VERSION 5.7 ;
BUSBITCHARS "[]" ;
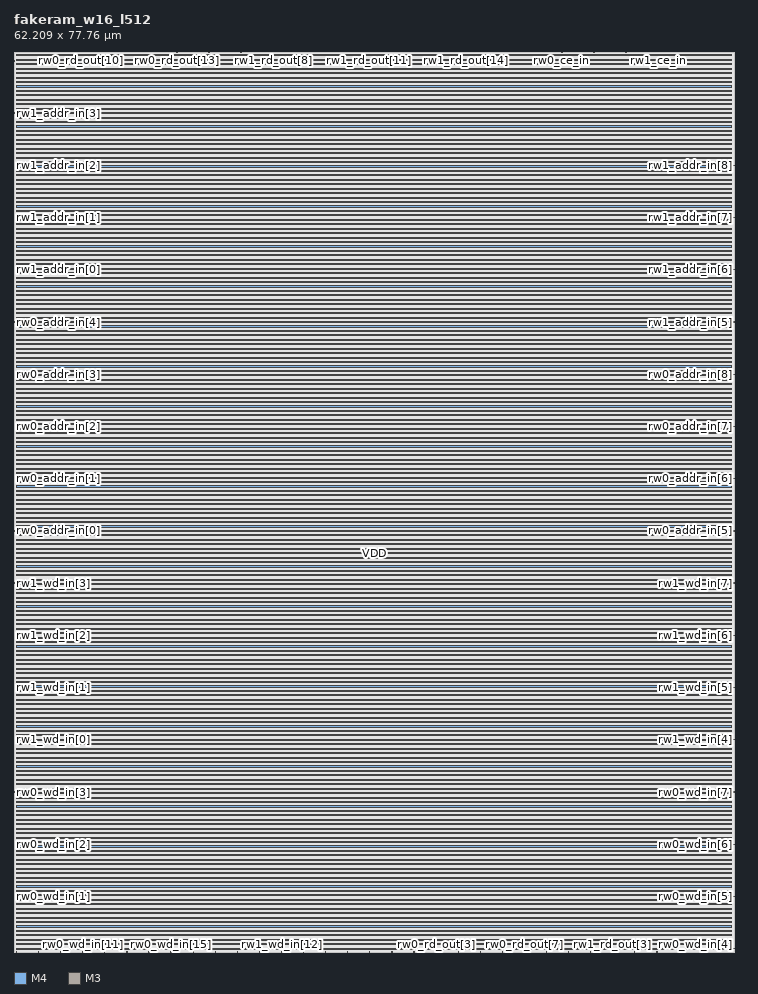
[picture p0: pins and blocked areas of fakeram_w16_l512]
MACRO fakeram_w16_l512
  FOREIGN fakeram_w16_l512 0 0 ;
  SYMMETRY X Y R90 ;
  SIZE 62.209 BY 77.760 ;
  CLASS BLOCK ;
  PIN rw0_wd_in[0]
    DIRECTION INPUT ;
    USE SIGNAL ;
    SHAPE ABUTMENT ;
    PORT
      LAYER M4 ;
      RECT 0.000 0.276 0.072 0.300 ;
    END
  END rw0_wd_in[0]
  PIN rw0_wd_in[1]
    DIRECTION INPUT ;
    USE SIGNAL ;
    SHAPE ABUTMENT ;
    PORT
      LAYER M4 ;
      RECT 0.000 4.788 0.072 4.812 ;
    END
  END rw0_wd_in[1]
  PIN rw0_wd_in[2]
    DIRECTION INPUT ;
    USE SIGNAL ;
    SHAPE ABUTMENT ;
    PORT
      LAYER M4 ;
      RECT 0.000 9.300 0.072 9.324 ;
    END
  END rw0_wd_in[2]
  PIN rw0_wd_in[3]
    DIRECTION INPUT ;
    USE SIGNAL ;
    SHAPE ABUTMENT ;
    PORT
      LAYER M4 ;
      RECT 0.000 13.812 0.072 13.836 ;
    END
  END rw0_wd_in[3]
  PIN rw0_wd_in[4]
    DIRECTION INPUT ;
    USE SIGNAL ;
    SHAPE ABUTMENT ;
    PORT
      LAYER M4 ;
      RECT 62.137 0.276 62.209 0.300 ;
    END
  END rw0_wd_in[4]
  PIN rw0_wd_in[5]
    DIRECTION INPUT ;
    USE SIGNAL ;
    SHAPE ABUTMENT ;
    PORT
      LAYER M4 ;
      RECT 62.137 4.788 62.209 4.812 ;
    END
  END rw0_wd_in[5]
  PIN rw0_wd_in[6]
    DIRECTION INPUT ;
    USE SIGNAL ;
    SHAPE ABUTMENT ;
    PORT
      LAYER M4 ;
      RECT 62.137 9.300 62.209 9.324 ;
    END
  END rw0_wd_in[6]
  PIN rw0_wd_in[7]
    DIRECTION INPUT ;
    USE SIGNAL ;
    SHAPE ABUTMENT ;
    PORT
      LAYER M4 ;
      RECT 62.137 13.812 62.209 13.836 ;
    END
  END rw0_wd_in[7]
  PIN rw0_wd_in[8]
    DIRECTION INPUT ;
    USE SIGNAL ;
    SHAPE ABUTMENT ;
    PORT
      LAYER M3 ;
      RECT 0.207 0.000 0.225 0.054 ;
    END
  END rw0_wd_in[8]
  PIN rw0_wd_in[9]
    DIRECTION INPUT ;
    USE SIGNAL ;
    SHAPE ABUTMENT ;
    PORT
      LAYER M3 ;
      RECT 2.115 0.000 2.133 0.054 ;
    END
  END rw0_wd_in[9]
  PIN rw0_wd_in[10]
    DIRECTION INPUT ;
    USE SIGNAL ;
    SHAPE ABUTMENT ;
    PORT
      LAYER M3 ;
      RECT 4.023 0.000 4.041 0.054 ;
    END
  END rw0_wd_in[10]
  PIN rw0_wd_in[11]
    DIRECTION INPUT ;
    USE SIGNAL ;
    SHAPE ABUTMENT ;
    PORT
      LAYER M3 ;
      RECT 5.931 0.000 5.949 0.054 ;
    END
  END rw0_wd_in[11]
  PIN rw0_wd_in[12]
    DIRECTION INPUT ;
    USE SIGNAL ;
    SHAPE ABUTMENT ;
    PORT
      LAYER M3 ;
      RECT 7.839 0.000 7.857 0.054 ;
    END
  END rw0_wd_in[12]
  PIN rw0_wd_in[13]
    DIRECTION INPUT ;
    USE SIGNAL ;
    SHAPE ABUTMENT ;
    PORT
      LAYER M3 ;
      RECT 9.747 0.000 9.765 0.054 ;
    END
  END rw0_wd_in[13]
  PIN rw0_wd_in[14]
    DIRECTION INPUT ;
    USE SIGNAL ;
    SHAPE ABUTMENT ;
    PORT
      LAYER M3 ;
      RECT 11.655 0.000 11.673 0.054 ;
    END
  END rw0_wd_in[14]
  PIN rw0_wd_in[15]
    DIRECTION INPUT ;
    USE SIGNAL ;
    SHAPE ABUTMENT ;
    PORT
      LAYER M3 ;
      RECT 13.563 0.000 13.581 0.054 ;
    END
  END rw0_wd_in[15]
  PIN rw1_wd_in[0]
    DIRECTION INPUT ;
    USE SIGNAL ;
    SHAPE ABUTMENT ;
    PORT
      LAYER M4 ;
      RECT 0.000 18.324 0.072 18.348 ;
    END
  END rw1_wd_in[0]
  PIN rw1_wd_in[1]
    DIRECTION INPUT ;
    USE SIGNAL ;
    SHAPE ABUTMENT ;
    PORT
      LAYER M4 ;
      RECT 0.000 22.836 0.072 22.860 ;
    END
  END rw1_wd_in[1]
  PIN rw1_wd_in[2]
    DIRECTION INPUT ;
    USE SIGNAL ;
    SHAPE ABUTMENT ;
    PORT
      LAYER M4 ;
      RECT 0.000 27.348 0.072 27.372 ;
    END
  END rw1_wd_in[2]
  PIN rw1_wd_in[3]
    DIRECTION INPUT ;
    USE SIGNAL ;
    SHAPE ABUTMENT ;
    PORT
      LAYER M4 ;
      RECT 0.000 31.860 0.072 31.884 ;
    END
  END rw1_wd_in[3]
  PIN rw1_wd_in[4]
    DIRECTION INPUT ;
    USE SIGNAL ;
    SHAPE ABUTMENT ;
    PORT
      LAYER M4 ;
      RECT 62.137 18.324 62.209 18.348 ;
    END
  END rw1_wd_in[4]
  PIN rw1_wd_in[5]
    DIRECTION INPUT ;
    USE SIGNAL ;
    SHAPE ABUTMENT ;
    PORT
      LAYER M4 ;
      RECT 62.137 22.836 62.209 22.860 ;
    END
  END rw1_wd_in[5]
  PIN rw1_wd_in[6]
    DIRECTION INPUT ;
    USE SIGNAL ;
    SHAPE ABUTMENT ;
    PORT
      LAYER M4 ;
      RECT 62.137 27.348 62.209 27.372 ;
    END
  END rw1_wd_in[6]
  PIN rw1_wd_in[7]
    DIRECTION INPUT ;
    USE SIGNAL ;
    SHAPE ABUTMENT ;
    PORT
      LAYER M4 ;
      RECT 62.137 31.860 62.209 31.884 ;
    END
  END rw1_wd_in[7]
  PIN rw1_wd_in[8]
    DIRECTION INPUT ;
    USE SIGNAL ;
    SHAPE ABUTMENT ;
    PORT
      LAYER M3 ;
      RECT 15.471 0.000 15.489 0.054 ;
    END
  END rw1_wd_in[8]
  PIN rw1_wd_in[9]
    DIRECTION INPUT ;
    USE SIGNAL ;
    SHAPE ABUTMENT ;
    PORT
      LAYER M3 ;
      RECT 17.379 0.000 17.397 0.054 ;
    END
  END rw1_wd_in[9]
  PIN rw1_wd_in[10]
    DIRECTION INPUT ;
    USE SIGNAL ;
    SHAPE ABUTMENT ;
    PORT
      LAYER M3 ;
      RECT 19.287 0.000 19.305 0.054 ;
    END
  END rw1_wd_in[10]
  PIN rw1_wd_in[11]
    DIRECTION INPUT ;
    USE SIGNAL ;
    SHAPE ABUTMENT ;
    PORT
      LAYER M3 ;
      RECT 21.195 0.000 21.213 0.054 ;
    END
  END rw1_wd_in[11]
  PIN rw1_wd_in[12]
    DIRECTION INPUT ;
    USE SIGNAL ;
    SHAPE ABUTMENT ;
    PORT
      LAYER M3 ;
      RECT 23.103 0.000 23.121 0.054 ;
    END
  END rw1_wd_in[12]
  PIN rw1_wd_in[13]
    DIRECTION INPUT ;
    USE SIGNAL ;
    SHAPE ABUTMENT ;
    PORT
      LAYER M3 ;
      RECT 25.011 0.000 25.029 0.054 ;
    END
  END rw1_wd_in[13]
  PIN rw1_wd_in[14]
    DIRECTION INPUT ;
    USE SIGNAL ;
    SHAPE ABUTMENT ;
    PORT
      LAYER M3 ;
      RECT 26.919 0.000 26.937 0.054 ;
    END
  END rw1_wd_in[14]
  PIN rw1_wd_in[15]
    DIRECTION INPUT ;
    USE SIGNAL ;
    SHAPE ABUTMENT ;
    PORT
      LAYER M3 ;
      RECT 28.827 0.000 28.845 0.054 ;
    END
  END rw1_wd_in[15]
  PIN rw0_rd_out[0]
    DIRECTION OUTPUT ;
    USE SIGNAL ;
    SHAPE ABUTMENT ;
    PORT
      LAYER M3 ;
      RECT 30.735 0.000 30.753 0.054 ;
    END
  END rw0_rd_out[0]
  PIN rw0_rd_out[1]
    DIRECTION OUTPUT ;
    USE SIGNAL ;
    SHAPE ABUTMENT ;
    PORT
      LAYER M3 ;
      RECT 32.643 0.000 32.661 0.054 ;
    END
  END rw0_rd_out[1]
  PIN rw0_rd_out[2]
    DIRECTION OUTPUT ;
    USE SIGNAL ;
    SHAPE ABUTMENT ;
    PORT
      LAYER M3 ;
      RECT 34.551 0.000 34.569 0.054 ;
    END
  END rw0_rd_out[2]
  PIN rw0_rd_out[3]
    DIRECTION OUTPUT ;
    USE SIGNAL ;
    SHAPE ABUTMENT ;
    PORT
      LAYER M3 ;
      RECT 36.459 0.000 36.477 0.054 ;
    END
  END rw0_rd_out[3]
  PIN rw0_rd_out[4]
    DIRECTION OUTPUT ;
    USE SIGNAL ;
    SHAPE ABUTMENT ;
    PORT
      LAYER M3 ;
      RECT 38.367 0.000 38.385 0.054 ;
    END
  END rw0_rd_out[4]
  PIN rw0_rd_out[5]
    DIRECTION OUTPUT ;
    USE SIGNAL ;
    SHAPE ABUTMENT ;
    PORT
      LAYER M3 ;
      RECT 40.275 0.000 40.293 0.054 ;
    END
  END rw0_rd_out[5]
  PIN rw0_rd_out[6]
    DIRECTION OUTPUT ;
    USE SIGNAL ;
    SHAPE ABUTMENT ;
    PORT
      LAYER M3 ;
      RECT 42.183 0.000 42.201 0.054 ;
    END
  END rw0_rd_out[6]
  PIN rw0_rd_out[7]
    DIRECTION OUTPUT ;
    USE SIGNAL ;
    SHAPE ABUTMENT ;
    PORT
      LAYER M3 ;
      RECT 44.091 0.000 44.109 0.054 ;
    END
  END rw0_rd_out[7]
  PIN rw0_rd_out[8]
    DIRECTION OUTPUT ;
    USE SIGNAL ;
    SHAPE ABUTMENT ;
    PORT
      LAYER M3 ;
      RECT 0.207 77.706 0.225 77.760 ;
    END
  END rw0_rd_out[8]
  PIN rw0_rd_out[9]
    DIRECTION OUTPUT ;
    USE SIGNAL ;
    SHAPE ABUTMENT ;
    PORT
      LAYER M3 ;
      RECT 2.979 77.706 2.997 77.760 ;
    END
  END rw0_rd_out[9]
  PIN rw0_rd_out[10]
    DIRECTION OUTPUT ;
    USE SIGNAL ;
    SHAPE ABUTMENT ;
    PORT
      LAYER M3 ;
      RECT 5.751 77.706 5.769 77.760 ;
    END
  END rw0_rd_out[10]
  PIN rw0_rd_out[11]
    DIRECTION OUTPUT ;
    USE SIGNAL ;
    SHAPE ABUTMENT ;
    PORT
      LAYER M3 ;
      RECT 8.523 77.706 8.541 77.760 ;
    END
  END rw0_rd_out[11]
  PIN rw0_rd_out[12]
    DIRECTION OUTPUT ;
    USE SIGNAL ;
    SHAPE ABUTMENT ;
    PORT
      LAYER M3 ;
      RECT 11.295 77.706 11.313 77.760 ;
    END
  END rw0_rd_out[12]
  PIN rw0_rd_out[13]
    DIRECTION OUTPUT ;
    USE SIGNAL ;
    SHAPE ABUTMENT ;
    PORT
      LAYER M3 ;
      RECT 14.067 77.706 14.085 77.760 ;
    END
  END rw0_rd_out[13]
  PIN rw0_rd_out[14]
    DIRECTION OUTPUT ;
    USE SIGNAL ;
    SHAPE ABUTMENT ;
    PORT
      LAYER M3 ;
      RECT 16.839 77.706 16.857 77.760 ;
    END
  END rw0_rd_out[14]
  PIN rw0_rd_out[15]
    DIRECTION OUTPUT ;
    USE SIGNAL ;
    SHAPE ABUTMENT ;
    PORT
      LAYER M3 ;
      RECT 19.611 77.706 19.629 77.760 ;
    END
  END rw0_rd_out[15]
  PIN rw1_rd_out[0]
    DIRECTION OUTPUT ;
    USE SIGNAL ;
    SHAPE ABUTMENT ;
    PORT
      LAYER M3 ;
      RECT 45.999 0.000 46.017 0.054 ;
    END
  END rw1_rd_out[0]
  PIN rw1_rd_out[1]
    DIRECTION OUTPUT ;
    USE SIGNAL ;
    SHAPE ABUTMENT ;
    PORT
      LAYER M3 ;
      RECT 47.907 0.000 47.925 0.054 ;
    END
  END rw1_rd_out[1]
  PIN rw1_rd_out[2]
    DIRECTION OUTPUT ;
    USE SIGNAL ;
    SHAPE ABUTMENT ;
    PORT
      LAYER M3 ;
      RECT 49.815 0.000 49.833 0.054 ;
    END
  END rw1_rd_out[2]
  PIN rw1_rd_out[3]
    DIRECTION OUTPUT ;
    USE SIGNAL ;
    SHAPE ABUTMENT ;
    PORT
      LAYER M3 ;
      RECT 51.723 0.000 51.741 0.054 ;
    END
  END rw1_rd_out[3]
  PIN rw1_rd_out[4]
    DIRECTION OUTPUT ;
    USE SIGNAL ;
    SHAPE ABUTMENT ;
    PORT
      LAYER M3 ;
      RECT 53.631 0.000 53.649 0.054 ;
    END
  END rw1_rd_out[4]
  PIN rw1_rd_out[5]
    DIRECTION OUTPUT ;
    USE SIGNAL ;
    SHAPE ABUTMENT ;
    PORT
      LAYER M3 ;
      RECT 55.539 0.000 55.557 0.054 ;
    END
  END rw1_rd_out[5]
  PIN rw1_rd_out[6]
    DIRECTION OUTPUT ;
    USE SIGNAL ;
    SHAPE ABUTMENT ;
    PORT
      LAYER M3 ;
      RECT 57.447 0.000 57.465 0.054 ;
    END
  END rw1_rd_out[6]
  PIN rw1_rd_out[7]
    DIRECTION OUTPUT ;
    USE SIGNAL ;
    SHAPE ABUTMENT ;
    PORT
      LAYER M3 ;
      RECT 59.355 0.000 59.373 0.054 ;
    END
  END rw1_rd_out[7]
  PIN rw1_rd_out[8]
    DIRECTION OUTPUT ;
    USE SIGNAL ;
    SHAPE ABUTMENT ;
    PORT
      LAYER M3 ;
      RECT 22.383 77.706 22.401 77.760 ;
    END
  END rw1_rd_out[8]
  PIN rw1_rd_out[9]
    DIRECTION OUTPUT ;
    USE SIGNAL ;
    SHAPE ABUTMENT ;
    PORT
      LAYER M3 ;
      RECT 25.155 77.706 25.173 77.760 ;
    END
  END rw1_rd_out[9]
  PIN rw1_rd_out[10]
    DIRECTION OUTPUT ;
    USE SIGNAL ;
    SHAPE ABUTMENT ;
    PORT
      LAYER M3 ;
      RECT 27.927 77.706 27.945 77.760 ;
    END
  END rw1_rd_out[10]
  PIN rw1_rd_out[11]
    DIRECTION OUTPUT ;
    USE SIGNAL ;
    SHAPE ABUTMENT ;
    PORT
      LAYER M3 ;
      RECT 30.699 77.706 30.717 77.760 ;
    END
  END rw1_rd_out[11]
  PIN rw1_rd_out[12]
    DIRECTION OUTPUT ;
    USE SIGNAL ;
    SHAPE ABUTMENT ;
    PORT
      LAYER M3 ;
      RECT 33.471 77.706 33.489 77.760 ;
    END
  END rw1_rd_out[12]
  PIN rw1_rd_out[13]
    DIRECTION OUTPUT ;
    USE SIGNAL ;
    SHAPE ABUTMENT ;
    PORT
      LAYER M3 ;
      RECT 36.243 77.706 36.261 77.760 ;
    END
  END rw1_rd_out[13]
  PIN rw1_rd_out[14]
    DIRECTION OUTPUT ;
    USE SIGNAL ;
    SHAPE ABUTMENT ;
    PORT
      LAYER M3 ;
      RECT 39.015 77.706 39.033 77.760 ;
    END
  END rw1_rd_out[14]
  PIN rw1_rd_out[15]
    DIRECTION OUTPUT ;
    USE SIGNAL ;
    SHAPE ABUTMENT ;
    PORT
      LAYER M3 ;
      RECT 41.787 77.706 41.805 77.760 ;
    END
  END rw1_rd_out[15]
  PIN rw0_addr_in[0]
    DIRECTION INPUT ;
    USE SIGNAL ;
    SHAPE ABUTMENT ;
    PORT
      LAYER M4 ;
      RECT 0.000 36.372 0.072 36.396 ;
    END
  END rw0_addr_in[0]
  PIN rw0_addr_in[1]
    DIRECTION INPUT ;
    USE SIGNAL ;
    SHAPE ABUTMENT ;
    PORT
      LAYER M4 ;
      RECT 0.000 40.884 0.072 40.908 ;
    END
  END rw0_addr_in[1]
  PIN rw0_addr_in[2]
    DIRECTION INPUT ;
    USE SIGNAL ;
    SHAPE ABUTMENT ;
    PORT
      LAYER M4 ;
      RECT 0.000 45.396 0.072 45.420 ;
    END
  END rw0_addr_in[2]
  PIN rw0_addr_in[3]
    DIRECTION INPUT ;
    USE SIGNAL ;
    SHAPE ABUTMENT ;
    PORT
      LAYER M4 ;
      RECT 0.000 49.908 0.072 49.932 ;
    END
  END rw0_addr_in[3]
  PIN rw0_addr_in[4]
    DIRECTION INPUT ;
    USE SIGNAL ;
    SHAPE ABUTMENT ;
    PORT
      LAYER M4 ;
      RECT 0.000 54.420 0.072 54.444 ;
    END
  END rw0_addr_in[4]
  PIN rw0_addr_in[5]
    DIRECTION INPUT ;
    USE SIGNAL ;
    SHAPE ABUTMENT ;
    PORT
      LAYER M4 ;
      RECT 62.137 36.372 62.209 36.396 ;
    END
  END rw0_addr_in[5]
  PIN rw0_addr_in[6]
    DIRECTION INPUT ;
    USE SIGNAL ;
    SHAPE ABUTMENT ;
    PORT
      LAYER M4 ;
      RECT 62.137 40.884 62.209 40.908 ;
    END
  END rw0_addr_in[6]
  PIN rw0_addr_in[7]
    DIRECTION INPUT ;
    USE SIGNAL ;
    SHAPE ABUTMENT ;
    PORT
      LAYER M4 ;
      RECT 62.137 45.396 62.209 45.420 ;
    END
  END rw0_addr_in[7]
  PIN rw0_addr_in[8]
    DIRECTION INPUT ;
    USE SIGNAL ;
    SHAPE ABUTMENT ;
    PORT
      LAYER M4 ;
      RECT 62.137 49.908 62.209 49.932 ;
    END
  END rw0_addr_in[8]
  PIN rw1_addr_in[0]
    DIRECTION INPUT ;
    USE SIGNAL ;
    SHAPE ABUTMENT ;
    PORT
      LAYER M4 ;
      RECT 0.000 58.932 0.072 58.956 ;
    END
  END rw1_addr_in[0]
  PIN rw1_addr_in[1]
    DIRECTION INPUT ;
    USE SIGNAL ;
    SHAPE ABUTMENT ;
    PORT
      LAYER M4 ;
      RECT 0.000 63.444 0.072 63.468 ;
    END
  END rw1_addr_in[1]
  PIN rw1_addr_in[2]
    DIRECTION INPUT ;
    USE SIGNAL ;
    SHAPE ABUTMENT ;
    PORT
      LAYER M4 ;
      RECT 0.000 67.956 0.072 67.980 ;
    END
  END rw1_addr_in[2]
  PIN rw1_addr_in[3]
    DIRECTION INPUT ;
    USE SIGNAL ;
    SHAPE ABUTMENT ;
    PORT
      LAYER M4 ;
      RECT 0.000 72.468 0.072 72.492 ;
    END
  END rw1_addr_in[3]
  PIN rw1_addr_in[4]
    DIRECTION INPUT ;
    USE SIGNAL ;
    SHAPE ABUTMENT ;
    PORT
      LAYER M4 ;
      RECT 0.000 76.980 0.072 77.004 ;
    END
  END rw1_addr_in[4]
  PIN rw1_addr_in[5]
    DIRECTION INPUT ;
    USE SIGNAL ;
    SHAPE ABUTMENT ;
    PORT
      LAYER M4 ;
      RECT 62.137 54.420 62.209 54.444 ;
    END
  END rw1_addr_in[5]
  PIN rw1_addr_in[6]
    DIRECTION INPUT ;
    USE SIGNAL ;
    SHAPE ABUTMENT ;
    PORT
      LAYER M4 ;
      RECT 62.137 58.932 62.209 58.956 ;
    END
  END rw1_addr_in[6]
  PIN rw1_addr_in[7]
    DIRECTION INPUT ;
    USE SIGNAL ;
    SHAPE ABUTMENT ;
    PORT
      LAYER M4 ;
      RECT 62.137 63.444 62.209 63.468 ;
    END
  END rw1_addr_in[7]
  PIN rw1_addr_in[8]
    DIRECTION INPUT ;
    USE SIGNAL ;
    SHAPE ABUTMENT ;
    PORT
      LAYER M4 ;
      RECT 62.137 67.956 62.209 67.980 ;
    END
  END rw1_addr_in[8]
  PIN rw0_we_in
    DIRECTION INPUT ;
    USE SIGNAL ;
    SHAPE ABUTMENT ;
    PORT
      LAYER M3 ;
      RECT 44.559 77.706 44.577 77.760 ;
    END
  END rw0_we_in
  PIN rw0_ce_in
    DIRECTION INPUT ;
    USE SIGNAL ;
    SHAPE ABUTMENT ;
    PORT
      LAYER M3 ;
      RECT 47.331 77.706 47.349 77.760 ;
    END
  END rw0_ce_in
  PIN rw0_clk
    DIRECTION INPUT ;
    USE SIGNAL ;
    SHAPE ABUTMENT ;
    PORT
      LAYER M3 ;
      RECT 50.103 77.706 50.121 77.760 ;
    END
  END rw0_clk
  PIN rw1_we_in
    DIRECTION INPUT ;
    USE SIGNAL ;
    SHAPE ABUTMENT ;
    PORT
      LAYER M3 ;
      RECT 52.875 77.706 52.893 77.760 ;
    END
  END rw1_we_in
  PIN rw1_ce_in
    DIRECTION INPUT ;
    USE SIGNAL ;
    SHAPE ABUTMENT ;
    PORT
      LAYER M3 ;
      RECT 55.647 77.706 55.665 77.760 ;
    END
  END rw1_ce_in
  PIN rw1_clk
    DIRECTION INPUT ;
    USE SIGNAL ;
    SHAPE ABUTMENT ;
    PORT
      LAYER M3 ;
      RECT 58.419 77.706 58.437 77.760 ;
    END
  END rw1_clk
  PIN VSS
    DIRECTION INOUT ;
    USE GROUND ;
    PORT
      LAYER M4 ;
      RECT 0.216 0.240 61.993 0.336 ;
      RECT 0.216 1.008 61.993 1.104 ;
      RECT 0.216 1.776 61.993 1.872 ;
      RECT 0.216 2.544 61.993 2.640 ;
      RECT 0.216 3.312 61.993 3.408 ;
      RECT 0.216 4.080 61.993 4.176 ;
      RECT 0.216 4.848 61.993 4.944 ;
      RECT 0.216 5.616 61.993 5.712 ;
      RECT 0.216 6.384 61.993 6.480 ;
      RECT 0.216 7.152 61.993 7.248 ;
      RECT 0.216 7.920 61.993 8.016 ;
      RECT 0.216 8.688 61.993 8.784 ;
      RECT 0.216 9.456 61.993 9.552 ;
      RECT 0.216 10.224 61.993 10.320 ;
      RECT 0.216 10.992 61.993 11.088 ;
      RECT 0.216 11.760 61.993 11.856 ;
      RECT 0.216 12.528 61.993 12.624 ;
      RECT 0.216 13.296 61.993 13.392 ;
      RECT 0.216 14.064 61.993 14.160 ;
      RECT 0.216 14.832 61.993 14.928 ;
      RECT 0.216 15.600 61.993 15.696 ;
      RECT 0.216 16.368 61.993 16.464 ;
      RECT 0.216 17.136 61.993 17.232 ;
      RECT 0.216 17.904 61.993 18.000 ;
      RECT 0.216 18.672 61.993 18.768 ;
      RECT 0.216 19.440 61.993 19.536 ;
      RECT 0.216 20.208 61.993 20.304 ;
      RECT 0.216 20.976 61.993 21.072 ;
      RECT 0.216 21.744 61.993 21.840 ;
      RECT 0.216 22.512 61.993 22.608 ;
      RECT 0.216 23.280 61.993 23.376 ;
      RECT 0.216 24.048 61.993 24.144 ;
      RECT 0.216 24.816 61.993 24.912 ;
      RECT 0.216 25.584 61.993 25.680 ;
      RECT 0.216 26.352 61.993 26.448 ;
      RECT 0.216 27.120 61.993 27.216 ;
      RECT 0.216 27.888 61.993 27.984 ;
      RECT 0.216 28.656 61.993 28.752 ;
      RECT 0.216 29.424 61.993 29.520 ;
      RECT 0.216 30.192 61.993 30.288 ;
      RECT 0.216 30.960 61.993 31.056 ;
      RECT 0.216 31.728 61.993 31.824 ;
      RECT 0.216 32.496 61.993 32.592 ;
      RECT 0.216 33.264 61.993 33.360 ;
      RECT 0.216 34.032 61.993 34.128 ;
      RECT 0.216 34.800 61.993 34.896 ;
      RECT 0.216 35.568 61.993 35.664 ;
      RECT 0.216 36.336 61.993 36.432 ;
      RECT 0.216 37.104 61.993 37.200 ;
      RECT 0.216 37.872 61.993 37.968 ;
      RECT 0.216 38.640 61.993 38.736 ;
      RECT 0.216 39.408 61.993 39.504 ;
      RECT 0.216 40.176 61.993 40.272 ;
      RECT 0.216 40.944 61.993 41.040 ;
      RECT 0.216 41.712 61.993 41.808 ;
      RECT 0.216 42.480 61.993 42.576 ;
      RECT 0.216 43.248 61.993 43.344 ;
      RECT 0.216 44.016 61.993 44.112 ;
      RECT 0.216 44.784 61.993 44.880 ;
      RECT 0.216 45.552 61.993 45.648 ;
      RECT 0.216 46.320 61.993 46.416 ;
      RECT 0.216 47.088 61.993 47.184 ;
      RECT 0.216 47.856 61.993 47.952 ;
      RECT 0.216 48.624 61.993 48.720 ;
      RECT 0.216 49.392 61.993 49.488 ;
      RECT 0.216 50.160 61.993 50.256 ;
      RECT 0.216 50.928 61.993 51.024 ;
      RECT 0.216 51.696 61.993 51.792 ;
      RECT 0.216 52.464 61.993 52.560 ;
      RECT 0.216 53.232 61.993 53.328 ;
      RECT 0.216 54.000 61.993 54.096 ;
      RECT 0.216 54.768 61.993 54.864 ;
      RECT 0.216 55.536 61.993 55.632 ;
      RECT 0.216 56.304 61.993 56.400 ;
      RECT 0.216 57.072 61.993 57.168 ;
      RECT 0.216 57.840 61.993 57.936 ;
      RECT 0.216 58.608 61.993 58.704 ;
      RECT 0.216 59.376 61.993 59.472 ;
      RECT 0.216 60.144 61.993 60.240 ;
      RECT 0.216 60.912 61.993 61.008 ;
      RECT 0.216 61.680 61.993 61.776 ;
      RECT 0.216 62.448 61.993 62.544 ;
      RECT 0.216 63.216 61.993 63.312 ;
      RECT 0.216 63.984 61.993 64.080 ;
      RECT 0.216 64.752 61.993 64.848 ;
      RECT 0.216 65.520 61.993 65.616 ;
      RECT 0.216 66.288 61.993 66.384 ;
      RECT 0.216 67.056 61.993 67.152 ;
      RECT 0.216 67.824 61.993 67.920 ;
      RECT 0.216 68.592 61.993 68.688 ;
      RECT 0.216 69.360 61.993 69.456 ;
      RECT 0.216 70.128 61.993 70.224 ;
      RECT 0.216 70.896 61.993 70.992 ;
      RECT 0.216 71.664 61.993 71.760 ;
      RECT 0.216 72.432 61.993 72.528 ;
      RECT 0.216 73.200 61.993 73.296 ;
      RECT 0.216 73.968 61.993 74.064 ;
      RECT 0.216 74.736 61.993 74.832 ;
      RECT 0.216 75.504 61.993 75.600 ;
      RECT 0.216 76.272 61.993 76.368 ;
      RECT 0.216 77.040 61.993 77.136 ;
    END
  END VSS
  PIN VDD
    DIRECTION INOUT ;
    USE POWER ;
    PORT
      LAYER M4 ;
      RECT 0.216 0.624 61.993 0.720 ;
      RECT 0.216 1.392 61.993 1.488 ;
      RECT 0.216 2.160 61.993 2.256 ;
      RECT 0.216 2.928 61.993 3.024 ;
      RECT 0.216 3.696 61.993 3.792 ;
      RECT 0.216 4.464 61.993 4.560 ;
      RECT 0.216 5.232 61.993 5.328 ;
      RECT 0.216 6.000 61.993 6.096 ;
      RECT 0.216 6.768 61.993 6.864 ;
      RECT 0.216 7.536 61.993 7.632 ;
      RECT 0.216 8.304 61.993 8.400 ;
      RECT 0.216 9.072 61.993 9.168 ;
      RECT 0.216 9.840 61.993 9.936 ;
      RECT 0.216 10.608 61.993 10.704 ;
      RECT 0.216 11.376 61.993 11.472 ;
      RECT 0.216 12.144 61.993 12.240 ;
      RECT 0.216 12.912 61.993 13.008 ;
      RECT 0.216 13.680 61.993 13.776 ;
      RECT 0.216 14.448 61.993 14.544 ;
      RECT 0.216 15.216 61.993 15.312 ;
      RECT 0.216 15.984 61.993 16.080 ;
      RECT 0.216 16.752 61.993 16.848 ;
      RECT 0.216 17.520 61.993 17.616 ;
      RECT 0.216 18.288 61.993 18.384 ;
      RECT 0.216 19.056 61.993 19.152 ;
      RECT 0.216 19.824 61.993 19.920 ;
      RECT 0.216 20.592 61.993 20.688 ;
      RECT 0.216 21.360 61.993 21.456 ;
      RECT 0.216 22.128 61.993 22.224 ;
      RECT 0.216 22.896 61.993 22.992 ;
      RECT 0.216 23.664 61.993 23.760 ;
      RECT 0.216 24.432 61.993 24.528 ;
      RECT 0.216 25.200 61.993 25.296 ;
      RECT 0.216 25.968 61.993 26.064 ;
      RECT 0.216 26.736 61.993 26.832 ;
      RECT 0.216 27.504 61.993 27.600 ;
      RECT 0.216 28.272 61.993 28.368 ;
      RECT 0.216 29.040 61.993 29.136 ;
      RECT 0.216 29.808 61.993 29.904 ;
      RECT 0.216 30.576 61.993 30.672 ;
      RECT 0.216 31.344 61.993 31.440 ;
      RECT 0.216 32.112 61.993 32.208 ;
      RECT 0.216 32.880 61.993 32.976 ;
      RECT 0.216 33.648 61.993 33.744 ;
      RECT 0.216 34.416 61.993 34.512 ;
      RECT 0.216 35.184 61.993 35.280 ;
      RECT 0.216 35.952 61.993 36.048 ;
      RECT 0.216 36.720 61.993 36.816 ;
      RECT 0.216 37.488 61.993 37.584 ;
      RECT 0.216 38.256 61.993 38.352 ;
      RECT 0.216 39.024 61.993 39.120 ;
      RECT 0.216 39.792 61.993 39.888 ;
      RECT 0.216 40.560 61.993 40.656 ;
      RECT 0.216 41.328 61.993 41.424 ;
      RECT 0.216 42.096 61.993 42.192 ;
      RECT 0.216 42.864 61.993 42.960 ;
      RECT 0.216 43.632 61.993 43.728 ;
      RECT 0.216 44.400 61.993 44.496 ;
      RECT 0.216 45.168 61.993 45.264 ;
      RECT 0.216 45.936 61.993 46.032 ;
      RECT 0.216 46.704 61.993 46.800 ;
      RECT 0.216 47.472 61.993 47.568 ;
      RECT 0.216 48.240 61.993 48.336 ;
      RECT 0.216 49.008 61.993 49.104 ;
      RECT 0.216 49.776 61.993 49.872 ;
      RECT 0.216 50.544 61.993 50.640 ;
      RECT 0.216 51.312 61.993 51.408 ;
      RECT 0.216 52.080 61.993 52.176 ;
      RECT 0.216 52.848 61.993 52.944 ;
      RECT 0.216 53.616 61.993 53.712 ;
      RECT 0.216 54.384 61.993 54.480 ;
      RECT 0.216 55.152 61.993 55.248 ;
      RECT 0.216 55.920 61.993 56.016 ;
      RECT 0.216 56.688 61.993 56.784 ;
      RECT 0.216 57.456 61.993 57.552 ;
      RECT 0.216 58.224 61.993 58.320 ;
      RECT 0.216 58.992 61.993 59.088 ;
      RECT 0.216 59.760 61.993 59.856 ;
      RECT 0.216 60.528 61.993 60.624 ;
      RECT 0.216 61.296 61.993 61.392 ;
      RECT 0.216 62.064 61.993 62.160 ;
      RECT 0.216 62.832 61.993 62.928 ;
      RECT 0.216 63.600 61.993 63.696 ;
      RECT 0.216 64.368 61.993 64.464 ;
      RECT 0.216 65.136 61.993 65.232 ;
      RECT 0.216 65.904 61.993 66.000 ;
      RECT 0.216 66.672 61.993 66.768 ;
      RECT 0.216 67.440 61.993 67.536 ;
      RECT 0.216 68.208 61.993 68.304 ;
      RECT 0.216 68.976 61.993 69.072 ;
      RECT 0.216 69.744 61.993 69.840 ;
      RECT 0.216 70.512 61.993 70.608 ;
      RECT 0.216 71.280 61.993 71.376 ;
      RECT 0.216 72.048 61.993 72.144 ;
      RECT 0.216 72.816 61.993 72.912 ;
      RECT 0.216 73.584 61.993 73.680 ;
      RECT 0.216 74.352 61.993 74.448 ;
      RECT 0.216 75.120 61.993 75.216 ;
      RECT 0.216 75.888 61.993 75.984 ;
      RECT 0.216 76.656 61.993 76.752 ;
      RECT 0.216 77.424 61.993 77.520 ;
    END
  END VDD
  OBS
    LAYER M1 ;
    RECT 0 0 62.209 77.760 ;
    LAYER M2 ;
    RECT 0 0 62.209 77.760 ;
    LAYER M3 ;
    RECT 0 0 62.209 77.760 ;
    LAYER M4 ;
    RECT 0 0 62.209 77.760 ;
  END
END fakeram_w16_l512

END LIBRARY
